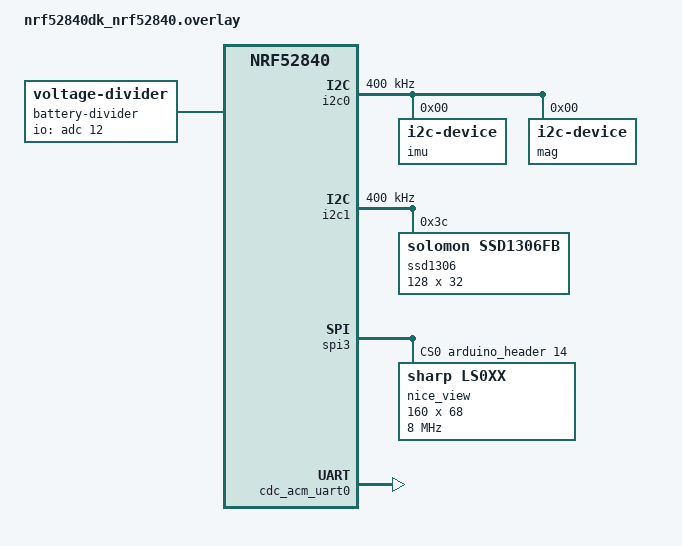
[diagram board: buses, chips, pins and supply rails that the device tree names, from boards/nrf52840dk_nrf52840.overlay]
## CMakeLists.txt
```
#
# Copyright (c) 2023 Nordic Semiconductor
#
# SPDX-License-Identifier: LicenseRef-Nordic-5-Clause
#
cmake_minimum_required(VERSION 3.20.0)

# Configure VERSION from repository branch and tag
find_package(Git)

if(GIT_EXECUTABLE)
  execute_process(
    COMMAND ${GIT_EXECUTABLE} branch --show-current
    WORKING_DIRECTORY ${CMAKE_SOURCE_DIR}
    OUTPUT_VARIABLE GIT_BRANCH
    )
  execute_process(
    COMMAND ${GIT_EXECUTABLE} describe --dirty --tags --long --match [0-9]*.[0-9]*.[0-9]*
    WORKING_DIRECTORY ${CMAKE_SOURCE_DIR}
    OUTPUT_VARIABLE GIT_VERSION
    )
endif()

if(GIT_BRANCH STREQUAL "")
  set(GIT_BRANCH unknown)
  message(WARNING "Unknown Git Branch")
endif()

if(GIT_VERSION STREQUAL "")
  set(GIT_VERSION 0.0.0-0)
  message(WARNING "Unknown Tag/Version")
endif()

string(STRIP ${GIT_BRANCH} GIT_BRANCH)
string(STRIP ${GIT_VERSION} GIT_VERSION)
string(REPLACE "-" ";" GIT_VERSION ${GIT_VERSION})
list(GET GIT_VERSION 0 GIT_RELEASE)
list(GET GIT_VERSION 1 GIT_TWEAK)
string(REPLACE "v" "" GIT_RELEASE ${GIT_RELEASE})
string(REPLACE "." ";" GIT_RELEASE ${GIT_RELEASE})
list(GET GIT_RELEASE 0 GIT_MAJOR)
list(GET GIT_RELEASE 1 GIT_MINOR)
list(GET GIT_RELEASE 2 GIT_PATCH)

configure_file(${CMAKE_SOURCE_DIR}/VERSION_SRC ${CMAKE_SOURCE_DIR}/VERSION @ONLY)

# Zephyr
find_package(Zephyr REQUIRED HINTS $ENV{ZEPHYR_BASE})
project(NONE)

# NORDIC SDK APP START
FILE(GLOB_RECURSE app_sources src/*.c)
target_sources(app PRIVATE ${app_sources})

# NORDIC SDK APP END

FILE(GLOB_RECURSE files vqf-c/src/*.c)
target_sources(app PRIVATE ${files})

target_include_directories(app PRIVATE src)
target_include_directories(app PRIVATE vqf-c/src)

# Force recompile for updated build timestamp
add_custom_target(touch_util_h ALL
    COMMAND ${CMAKE_COMMAND} -E touch ${CMAKE_SOURCE_DIR}/src/build_defines.h
)

# clangd wants compile_commands.json in the root of build directory
# try to find the build root clangd will be happy with
cmake_path(GET CMAKE_CURRENT_BINARY_DIR PARENT_PATH build_dir)
cmake_path(COMPARE ${CMAKE_CURRENT_LIST_DIR} NOT_EQUAL ${build_dir} build_dir_is_subdirectory)

if(build_dir_is_subdirectory)
  add_custom_target(link_target ALL
    COMMAND ${CMAKE_COMMAND} -E create_symlink ${CMAKE_CURRENT_BINARY_DIR}/compile_commands.json ${build_dir}/compile_commands.json)
endif()
```

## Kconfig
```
#
# Copyright (c) 2023 Nordic Semiconductor
#
# SPDX-License-Identifier: LicenseRef-Nordic-5-Clause
#

config USE_SLIMENRF_CONSOLE
    bool "Use basic console"
    default y
    help
        Use basic console for commands.

config BATTERY_CHARGER_HAS_NTC
    bool "Battery thermistor"
    help
      Flag for battery NTC thermistor availability.

choice
    prompt "Battery voltage mapping"
    default BATTERY_NO_MAPPING

config BATTERY_USE_REG_BUCK_MAPPING
    bool "Use buck regulator mapping (3.7V battery, DCDC)"
    help
      Use a constant power mapping for battery voltage.
      Preffered for systems with a buck regulator.
      Measured at a system voltage of 3.0V.

config BATTERY_USE_REG_LDO_MAPPING
    bool "Use LDO linear regulator mapping (3.7V battery, LDO)"
    help
      Use a constant current mapping for battery voltage.
      Preferred for systems with a linear regulator.

config BATTERY_NO_MAPPING
    bool "Disable battery voltage mapping"
    help
      Always map to 100% battery. Disables battery monitoring.

endchoice

config BATTERY_LOW_RUNTIME_THRESHOLD
    int "Low battery runtime threshold (ms)"
    default 10800000
    help
      Trigger low battery when estimated runtime falls below threshold.
      If estimated runtime is not available, low battery will trigger under 10% estimated state of charge.

choice
    prompt "Status LED color mapping"
    default LED_TRI_COLOR

config LED_RGB_COLOR
    bool "Use RGB color mapping"
    help
        Use RGB or RG color mapping for LED status if available.

config LED_TRI_COLOR
    bool "Use default color mapping"
    help
        Use the default color mapping for LED status.

endchoice

menu "Status LED default status color"
    depends on LED_RGB_COLOR

config LED_DEFAULT_COLOR_R
    int "Red value"
    range 0 10000
    default 4000
    depends on LED_RGB_COLOR
    help
        Red color for default status.
        Valid range is 0 to 10000.

config LED_DEFAULT_COLOR_G
    int "Green value"
    range 0 10000
    default 6000
    depends on LED_RGB_COLOR
    help
        Green color for default status.
        Valid range is 0 to 10000.

config LED_DEFAULT_COLOR_B
    int "Blue value"
    range 0 10000
    default 0
    depends on LED_RGB_COLOR
    help
        Blue color for default status.
        Valid range is 0 to 10000.

endmenu

config USER_EXTRA_ACTIONS
    bool "Multiple press actions"
    help
        Allow user to use multiple presses to calibrate, pair, or enter DFU.
        By default, pairing is available when holding down sw0 for 5 seconds.
        By default, DFU is available when holding down sw0 and plugging in a USB cable.

config IGNORE_RESET
    bool "Ignore reset"
    default y
    help
        If sw0 is available, don't perform any extra actions on reset.

config USER_SHUTDOWN
    bool "User shutdown support"
    default y
    help
        Allow user to use reset or sw0 to shutdown.

config USE_IMU_WAKE_UP
    bool "IMU wake up support"
    default y
    help
        Use IMU wake up state if IMU wake up is present.

config DELAY_SLEEP_ON_STATUS
    bool "Delay IMU wake up mode on status flags"
    default y
    depends on USE_IMU_WAKE_UP
    help
        Delay IMU wake up state if there is an active status flag or in pairing mode.

config WOM_USE_DCDC
    bool "Use DCDC in IMU wake up mode"
    depends on USE_IMU_WAKE_UP
    help
        Use DCDC instead of LDO in IMU wake up state if it is more efficient.

config CONNECTION_TIMEOUT_DELAY
    int "Connection timeout delay (ms)"
    default 600000
    depends on USER_SHUTDOWN
    help
        Connection timeout duration when receiver is not detected.

choice
    prompt "Sensor rotation"
    default SENSOR_ROTATION_90

config SENSOR_ROTATION_0
    bool "0 degrees"

config SENSOR_ROTATION_90
    bool "90 degrees"

config SENSOR_ROTATION_180
    bool "180 degrees"

config SENSOR_ROTATION_270
    bool "270 degrees"

config SENSOR_ROTATION_0_FLIPPED
    bool "0 degrees flipped"

config SENSOR_ROTATION_90_FLIPPED
    bool "90 degrees flipped"

config SENSOR_ROTATION_180_FLIPPED
    bool "180 degrees flipped"

config SENSOR_ROTATION_270_FLIPPED
    bool "270 degrees flipped"

endchoice

menu "Sensor power saving"

config SENSOR_LP_TIMEOUT
    int "Sensor low power delay (ms)"
    default 500
    help
        Low power timeout during no motion.

config SENSOR_USE_LOW_POWER_2
    bool "Use additional low power modes"
    help
        Use a higher latency sensor mode during no motion.

config USE_IMU_TIMEOUT
    bool "Use IMU wake up state"
    default y
    depends on USE_IMU_WAKE_UP
    help
        Use IMU wake up state during no motion.

config IMU_TIMEOUT_RAMP_MIN
    int "Sensor timeout minimum delay (ms)"
    default 5000
    depends on USE_IMU_TIMEOUT || SENSOR_USE_LOW_POWER_2
    help
        Minimum timeout during no motion. Initial period on wake up.

config IMU_TIMEOUT_RAMP_MAX
    int "Sensor timeout maximum delay (ms)"
    default 15000
    depends on USE_IMU_TIMEOUT || SENSOR_USE_LOW_POWER_2
    help
        Maximum timeout during no motion.

config USE_ACTIVE_TIMEOUT
    bool "Use activity timeout"
    default y
    depends on USE_IMU_WAKE_UP || USER_SHUTDOWN
    help
        Delay IMU wake up state or user shutdown during activity.

choice
    prompt "Activity timeout mode"
    default SLEEP_ON_ACTIVE_TIMEOUT
    depends on USE_ACTIVE_TIMEOUT

config SLEEP_ON_ACTIVE_TIMEOUT
    bool "IMU wake up"
    depends on USE_IMU_WAKE_UP
    help
        Use IMU wake up state when activity timeout elapses.

config SHUTDOWN_ON_ACTIVE_TIMEOUT
    bool "User shutdown"
    depends on USER_SHUTDOWN
    help
        Use user shutdown when activity timeout elapses.

endchoice

config ACTIVE_TIMEOUT_THRESHOLD
    int "Activity timeout threshold (ms)"
    default 15000
    depends on USE_ACTIVE_TIMEOUT
    help
        Trigger activity timeout after a certain threshold of activity.

config ACTIVE_TIMEOUT_DELAY
    int "Activity timeout delay (ms)"
    default 900000
    depends on USE_ACTIVE_TIMEOUT
    help
        Activity timeout duration when triggered.

endmenu

config SENSOR_ACCEL_ODR
    int "Accelerometer output data rate (Hz)"
    default 100
    help
        Requested accelerometer output data rate. Actual rate will be raised to the nearest supported rate.
        A higher rate will increase the time to read and process sensor data.

config SENSOR_GYRO_ODR
    int "Gyrometer output data rate (Hz)"
    default 200
    help
        Requested gyrometer output data rate. Actual rate will be raised to the nearest supported rate.
        A higher rate will increase the time to read and process sensor data.
        A lower rate is recommended for IMUs with poor gyrometer rate noise density. (e.g. BMI270, LSM6DS3TR-C)

config SENSOR_ACCEL_FS
    int "Accelerometer full scale (g)"
    default 4
    help
        Requested accelerometer full scale. Actual scale will be raised to the nearest supported scale.
        A lower scale may improve noise performance, but is more likely to saturate.

config SENSOR_GYRO_FS
    int "Gyrometer full scale (dps)"
    default 1000
    help
        Requested gyrometer full scale. Actual scale will be raised to the nearest supported scale.
        A lower scale may improve noise performance, but is more likely to saturate.

config SENSOR_USE_MAG
    bool "Magnetometer support"
    default y
    help
        Use magnetometer if it is present.

config USE_SENSOR_CLOCK
    bool "Use external IMU clock"
    default y
    help
        Use external IMU clock if it is present.

choice
    prompt "Sensor fusion"
    default SENSOR_USE_VQF
    help
        Select the sensor fusion method.

config SENSOR_USE_VQF
    bool "Use VQF"
    help
        Use VQF for sensor fusion.
        Based on Kalman filter.

endchoice

config SENSOR_USE_6_SIDE_CALIBRATION
    bool "Use 6-side calibration"
    default y
    depends on USE_SLIMENRF_CONSOLE
    help
        Use 6-side calibration for accelerometer.
        Calibration can be completed through the basic console.

config RADIO_TX_POWER
    int "Radio output power (dBm)"
    default 8
    help
        Radio output power level.
        A lower value may reduce power consumption.

config CONNECTION_OVER_HID
    bool "Use HID for data output"
    help
        Use HID if available.
        Otherwise, use ESB only.

choice CLOCK_SOURCE_LFCLK
    prompt "LF clock source for TDMA"
    default CLOCK_SOURCE_LFCLK_FULL_SWING
    help
        Chose which crystal or oscillator is connected
        to XL1/XL2 pins, if any. External 32.768kHz crystal
        or oscillator is recommended.

config CLOCK_SOURCE_LFCLK_XTAL
    bool "External passive crystal"

config CLOCK_SOURCE_LFCLK_LOW_SWING
    bool "External low-swing oscillator"

config CLOCK_SOURCE_LFCLK_FULL_SWING
    bool "External full-swing oscillator"

config CLOCK_SOURCE_LFCLK_SYNTH
    bool "Synthesized from internal HF clock (high power consumption)"

config CLOCK_SOURCE_LFCLK_RC
    bool "Internal RC clock (bad performance)"

endchoice

config BTF_DUT
    bool "Test mode for certification"

source "Kconfig.zephyr"
```

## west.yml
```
manifest:
  version: "1.2"
  projects:

    # nRF-Connect SDK
    - name: sdk-nrf
      path: nrf
      url: https://github.com/SlimeVR/sdk-nrf.git
      revision: v3.1-slimevr
      import: true
```

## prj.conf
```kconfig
#CONFIG_NCS_SAMPLES_DEFAULTS
CONFIG_ASSERT=y
CONFIG_ASSERT_NO_COND_INFO=y
CONFIG_ASSERT_NO_MSG_INFO=y
CONFIG_RESET_ON_FATAL_ERROR=y

CONFIG_NCS_APPLICATION_BOOT_BANNER_STRING="SlimeVR-Tracker-nRF"
#CONFIG_NCS_BOOT_BANNER=n
CONFIG_BOOT_BANNER=n

#need to enable for nRF54L
CONFIG_NRFX_DPPI10=y

CONFIG_ADC=y
CONFIG_ADC_NRFX_SAADC=y
CONFIG_FPU=y
CONFIG_I2C=y
CONFIG_SPI=y
CONFIG_PINCTRL=y
CONFIG_SENSOR=y
CONFIG_ESB=y

CONFIG_CMSIS_DSP=y
CONFIG_CMSIS_DSP_BASICMATH=y
CONFIG_CMSIS_DSP_CONTROLLER=y
CONFIG_CMSIS_DSP_FASTMATH=y
CONFIG_CMSIS_DSP_SUPPORT=y

CONFIG_NVS=y
CONFIG_NVS_LOOKUP_CACHE=y
CONFIG_NVS_INIT_BAD_MEMORY_REGION=y

CONFIG_POWEROFF=y
CONFIG_REBOOT=y

CONFIG_FLASH=y
CONFIG_FLASH_PAGE_LAYOUT=y
CONFIG_FLASH_MAP=y

CONFIG_SETTINGS=y
CONFIG_SETTINGS_RUNTIME=y
CONFIG_SETTINGS_NONE=y

CONFIG_MPU_ALLOW_FLASH_WRITE=y

CONFIG_RETAINED_MEM=y

CONFIG_USE_SEGGER_RTT=y
CONFIG_LOG=y
#CONFIG_PRINTK=n
CONFIG_LOG_MODE_DEFERRED=y
CONFIG_LOG_SPEED=y
CONFIG_LOG_BACKEND_RTT=y
CONFIG_CBPRINTF_FP_SUPPORT=y
CONFIG_ADC_LOG_LEVEL_OFF=y
CONFIG_LOG_FUNC_NAME_PREFIX_ERR=y
CONFIG_LOG_BUFFER_SIZE=8192
CONFIG_LOG_BACKEND_UART_AUTOSTART=y
CONFIG_LOG_PROCESS_THREAD_SLEEP_MS=50
CONFIG_LOG_PROCESS_THREAD_STACK_SIZE=1024

CONFIG_PWM=y
CONFIG_GPIO=y

CONFIG_CRC=y

CONFIG_NEWLIB_LIBC=y
#deprecated?
#CONFIG_NRFX_TIMER1=y

# Use uncalibrated RC clock on boot, will switch to external oscillator in the app after boot
CONFIG_CLOCK_CONTROL_NRF_K32SRC_RC=y
CONFIG_CLOCK_CONTROL_NRF_K32SRC_RC_CALIBRATION=y
CONFIG_CLOCK_CONTROL_NRF_K32SRC_SYNTH=n

# dont need it
CONFIG_CRYPTO=n

# set timeout for 25ms, sufficient for ~1000 bytes
CONFIG_I2C_NRFX_TRANSFER_TIMEOUT=25

CONFIG_USB_DEVICE_HID=y
CONFIG_USB_DEVICE_VID=0x1209
CONFIG_USB_DEVICE_PID=0x7692
CONFIG_USB_HID_BOOT_PROTOCOL=y
CONFIG_USB_DEVICE_INITIALIZE_AT_BOOT=n
CONFIG_USB_CDC_ACM=y
CONFIG_UART_INTERRUPT_DRIVEN=y
CONFIG_USB_WORKQUEUE_STACK_SIZE=512

CONFIG_SERIAL=y
CONFIG_CONSOLE=y
CONFIG_RTT_CONSOLE=y
CONFIG_UART_CONSOLE=y
CONFIG_UART_LINE_CTRL=y
# fit "write all <base64:173>"
CONFIG_CONSOLE_INPUT_MAX_LINE_LEN=256

CONFIG_USB_DRIVER_LOG_LEVEL_ERR=y
CONFIG_USB_DEVICE_LOG_LEVEL_ERR=y
CONFIG_USB_CDC_ACM_LOG_LEVEL_OFF=y

CONFIG_LOG_BACKEND_UART=y

CONFIG_CONSOLE_SUBSYS=y
CONFIG_CONSOLE_GETLINE=y

CONFIG_NVS_LOG_LEVEL_WRN=y
CONFIG_USB_HID_LOG_LEVEL_WRN=y

CONFIG_USB_DEVICE_SOF=y
CONFIG_USB_HID_REPORTS=256

#CONFIG_USB_HID_POLL_INTERVAL_MS=1
CONFIG_USB_HID_POLL_INTERVAL_MS=0
CONFIG_HID_INTERRUPT_EP_MPS=64
#CONFIG_ENABLE_HID_INT_OUT_EP=y

CONFIG_SYSTEM_WORKQUEUE_STACK_SIZE=4096
CONFIG_MAIN_STACK_SIZE=1024
#crashing on nrf54l at 512

CONFIG_THREAD_NAME=y

CONFIG_HEAP_MEM_POOL_SIZE=2048
CONFIG_ISR_STACK_SIZE=1024

CONFIG_PM_DEVICE=y

CONFIG_BASE64=y

#about 20KB saved
#CONFIG_LTO=y
#CONFIG_ISR_TABLES_LOCAL_DECLARATION=y

#CONFIG_USE_IMU_TIMEOUT=n

CONFIG_GPIO_LV164=y
CONFIG_LOG_MODE_IMMEDIATE=n

### Clock ###
CONFIG_CLOCK_CONTROL=y
CONFIG_CLOCK_CONTROL_NRF=y

CONFIG_NRFX_CLOCK=y
CONFIG_NRF_GRTC_TIMER=y
CONFIG_NRF_GRTC_START_SYSCOUNTER=y
CONFIG_NRFX_GRTC=y
CONFIG_NRFX_CLOCK_LF_SRC_RC=y

CONFIG_CLOCK_CONTROL_NRF_K32SRC_SYNTH=n
CONFIG_CLOCK_CONTROL_NRF_K32SRC_RC=y
CONFIG_CLOCK_CONTROL_NRF_K32SRC_XTAL=n

CONFIG_CLOCK_CONTROL_NRF_K32SRC_500PPM=y
CONFIG_CLOCK_CONTROL_NRF_K32SRC_RC_CALIBRATION=y
CONFIG_CLOCK_CONTROL_NRF_CALIBRATION_LF_ALWAYS_ON=y

CONFIG_SYS_CLOCK_HW_CYCLES_PER_SEC=1000000
CONFIG_SYS_CLOCK_TICKS_PER_SEC=32768
CONFIG_LED_STRIP=n

CONFIG_LOG_MODE_IMMEDIATE=n

CONFIG_EXCEPTION_STACK_TRACE=y
CONFIG_RESET_ON_FATAL_ERROR=n
CONFIG_THREAD_ANALYZER=y
CONFIG_THREAD_STACK_INFO=y
CONFIG_INIT_STACKS=y
CONFIG_HW_STACK_PROTECTION=y
```

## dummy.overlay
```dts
// dummy flash partitions for mcuboot compilation
&flash0 {
	partitions {
		compatible = "fixed-partitions";
		#address-cells = <1>;
		#size-cells = <1>;

		slot0_partition: partition@0 {
			reg = <0 1>;
		};
	};
};
```

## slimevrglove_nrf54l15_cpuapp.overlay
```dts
/* For more help, browse the devicetree documentation at https://docs.zephyrproject.org/latest/build/dts/index.html
 * You can also visit the nRF DeviceTree extension documentation at https://docs.nordicsemi.com/bundle/nrf-connect-vscode/page/guides/ncs_configure_app.html#devicetree-support-in-the-extension
 */
```

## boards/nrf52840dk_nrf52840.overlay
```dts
&pwm0_default {
	group1 {
		psels = <NRF_PSEL(PWM_OUT0, 0, 13)>,
			<NRF_PSEL(PWM_OUT1, 0, 14)>,
			<NRF_PSEL(PWM_OUT2, 0, 15)>;
		nordic,drive-mode = <NRF_DRIVE_D0S1>;
		nordic,invert;
	};
};

&pwm0_sleep {
	group1 {
		psels = <NRF_PSEL(PWM_OUT0, 0, 13)>,
			<NRF_PSEL(PWM_OUT1, 0, 14)>,
			<NRF_PSEL(PWM_OUT2, 0, 15)>;
	};
};

&i2c0_default {
	group1 {
		bias-disable;
	};
};

&i2c0_sleep {
	group1 {
		bias-disable;
	};
};

/ {
	chosen {
		zephyr,console = &cdc_acm_uart0;
		zephyr,shell-uart = &cdc_acm_uart0;
		zephyr,display = &nice_view;
	};

	pwmleds {
		pwm_led1: pwm_led_1 {
			pwms = <&pwm0 1 PWM_MSEC(20) PWM_POLARITY_INVERTED>;
		};
		pwm_led2: pwm_led_2 {
			pwms = <&pwm0 2 PWM_MSEC(20) PWM_POLARITY_INVERTED>;
		};
	};

	battery-divider {
		compatible = "voltage-divider";
		status = "okay";
		io-channels = <&adc 12>; // Measure VDDHDIV5
		output-ohms = <1>;
		full-ohms = <2>;
	};

	aliases {
		pwm-led1 = &pwm_led1;
		pwm-led2 = &pwm_led2;
	};
};

&i2c0 {
	compatible = "nordic,nrf-twim";
	zephyr,concat-buf-size = <1023>;
	zephyr,flash-buf-max-size = <1023>;
	clock-frequency = <I2C_BITRATE_FAST>;

	imu: imu@0 { // any address out of range (00, 7f, etc. will search all addresses and stored address first if available, specify an address here to search first otherwise
		compatible = "i2c-device";
		label = "imu";
		reg = <0>;
	};

	mag: mag@0 {
		compatible = "i2c-device";
		label = "mag";
		reg = <0>;
	};

};

&i2c1 {
	compatible = "nordic,nrf-twim";
	status = "okay";
	clock-frequency = <I2C_BITRATE_FAST>;
	zephyr,concat-buf-size = <4096>;

	ssd1306: ssd1306@3c {
		status = "okay";
		compatible = "solomon,ssd1306fb";
		reg = <0x3c>;
		width = <128>;
		height = <32>;
		segment-offset = <0>;
		page-offset = <0>;
		display-offset = <0>;
		multiplex-ratio = <31>;
		segment-remap;
		com-invdir;
		com-sequential;
		prechargep = <0x22>;
	};
};

&spi1 {
	status = "disabled";
};

&spi3 {
	status = "okay";
    cs-gpios = <&arduino_header 14 GPIO_ACTIVE_HIGH>;
    pinctrl-0 = <&spi2_default>;
    pinctrl-1 = <&spi2_sleep>;
    nice_view: ls0xx@0 {
        compatible = "sharp,ls0xx";
		spi-max-frequency = <DT_FREQ_M(8)>;
        reg = <0>;
        width = <160>;
        height = <68>;
    };
};

/delete-node/ &qspi;
/delete-node/ &spi2;

/*
&spi3 {
	status = "okay";
    cs-gpios = <&arduino_header 16 GPIO_ACTIVE_LOW>;
    pinctrl-0 = <&spi3_default>;
    pinctrl-1 = <&spi3_sleep>;
	imu_spi: imu_spi@0 {
		compatible = "vnd,spi-device";
		spi-max-frequency = <DT_FREQ_M(32)>;
		label = "imu-spi";
		reg = <0>;
	};
};
*/

&usbd {
	cdc_acm_uart0: cdc_acm_uart0 {
		compatible = "zephyr,cdc-acm-uart";
	};
};
```

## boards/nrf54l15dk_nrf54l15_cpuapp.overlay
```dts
&pinctrl {
	i2c0_default: i2c0_default {
		group1 {
			psels = <NRF_PSEL(TWIM_SDA, 1, 5)>,
				<NRF_PSEL(TWIM_SCL, 1, 7)>;
		};
	};

	i2c0_sleep: i2c0_sleep {
		group1 {
			psels = <NRF_PSEL(TWIM_SDA, 1, 5)>,
				<NRF_PSEL(TWIM_SCL, 1, 7)>;
			low-power-enable;
		};
	};
};

&pwm20_default {
	group1 {
		psels = <NRF_PSEL(PWM_OUT0, 1, 10)>,
			<NRF_PSEL(PWM_OUT1, 1, 14)>;
	};
};

&pwm20_sleep {
	group1 {
		psels = <NRF_PSEL(PWM_OUT0, 1, 10)>,
			<NRF_PSEL(PWM_OUT1, 1, 14)>;
	};
};

/ {
	pwmleds {
		pwm_led0: pwm_led_0 {
			pwms = <&pwm20 1 PWM_MSEC(20) PWM_POLARITY_NORMAL>;
		};
	};

	battery-divider {
		compatible = "voltage-divider";
		status = "okay";
		io-channels = <&adc 12>; // Measure VDDHDIV5
		output-ohms = <1>;
		full-ohms = <2>;
	};
};

&i2c20 {
	compatible = "nordic,nrf-twim";
	status = "okay";
	zephyr,concat-buf-size = <1023>;
	zephyr,flash-buf-max-size = <1023>;
	clock-frequency = <I2C_BITRATE_FAST>;
	pinctrl-0 = <&i2c0_default>;
	pinctrl-1 = <&i2c0_sleep>;
	pinctrl-names = "default", "sleep";

	imu: imu@0 { // any address out of range (00, 7f, etc. will search all addresses and stored address first if available, specify an address here to search first otherwise
		compatible = "i2c-device";
		label = "imu";
		reg = <0>;
	};

	mag: mag@0 {
		compatible = "i2c-device";
		label = "mag";
		reg = <0>;
	};
};

&spi00 {
	/delete-node/ mx25r6435f@0;

	imu_spi: imu_spi@0 {
		compatible = "vnd,spi-device";
		spi-max-frequency = <DT_FREQ_M(24)>;
		label = "imu-spi";
		reg = <0>;
	};
};

&uart20 {
	status = "disabled";
};
```

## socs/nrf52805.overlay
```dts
/ {
	sram0@20005800 {
		compatible = "zephyr,memory-region", "mmio-sram";
		reg = <0x20005800 DT_SIZE_K(2)>;
		zephyr,memory-region = "RetainedMem";
		status = "okay";

		retainedmem0: retainedmem {
			compatible = "zephyr,retained-ram";
			status = "okay";
		};
	};

	aliases {
		retainedmemdevice = &retainedmem0;
	};
};

&sram0 {
	/* Shrink SRAM size to avoid overlap with retained memory region */
	reg = <0x20000000 DT_SIZE_K(22)>;
};
```

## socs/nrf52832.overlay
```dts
/ {
	sram0@20007000 {
		compatible = "zephyr,memory-region", "mmio-sram";
		reg = <0x20007000 DT_SIZE_K(4)>;
		zephyr,memory-region = "RetainedMem";
		status = "okay";

		retainedmem0: retainedmem {
			compatible = "zephyr,retained-ram";
			status = "okay";
		};
	};

	aliases {
		retainedmemdevice = &retainedmem0;
	};
};

&sram0 {
	/* Shrink SRAM size to avoid overlap with retained memory region */
	reg = <0x20000000 DT_SIZE_K(28)>;
};
```

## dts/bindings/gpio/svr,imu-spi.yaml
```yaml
description: "imu with added properties"

compatible: "svr,imu-spi"

include: spi-device.yaml

properties:
  sensor-position:
    type: int
    required: false
    description: Value of sensor position as described in sensor_position.h
```

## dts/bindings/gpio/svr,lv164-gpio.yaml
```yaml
compatible: "svr,lv164-gpio"

description: "Driver to make reading from multiple imus easier"

include: [gpio-controller.yaml, base.yaml]

properties:
  dsb-gpios:
    type: phandle-array
    required: true
    description: Serial data input pin (DS) of the shift register.

  cp-gpios:
    type: phandle-array
    required: true
    description: Shift clock pin (CP) of the shift register.

  num-outputs:
    type: int
    required: true
    description: Number of output bits (8 for a single 74LV164, 16 if two are daisy-chained, etc).

  "#gpio-cells":
    const: 2

gpio-cells:
  - pin
  - flags
```

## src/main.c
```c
/*
	SlimeVR Code is placed under the MIT license
	Copyright (c) 2025 SlimeVR Contributors

	Permission is hereby granted, free of charge, to any person obtaining a copy
	of this software and associated documentation files (the "Software"), to deal
	in the Software without restriction, including without limitation the rights
	to use, copy, modify, merge, publish, distribute, sublicense, and/or sell
	copies of the Software, and to permit persons to whom the Software is
	furnished to do so, subject to the following conditions:

	The above copyright notice and this permission notice shall be included in
	all copies or substantial portions of the Software.

	THE SOFTWARE IS PROVIDED "AS IS", WITHOUT WARRANTY OF ANY KIND, EXPRESS OR
	IMPLIED, INCLUDING BUT NOT LIMITED TO THE WARRANTIES OF MERCHANTABILITY,
	FITNESS FOR A PARTICULAR PURPOSE AND NONINFRINGEMENT. IN NO EVENT SHALL THE
	AUTHORS OR COPYRIGHT HOLDERS BE LIABLE FOR ANY CLAIM, DAMAGES OR OTHER
	LIABILITY, WHETHER IN AN ACTION OF CONTRACT, TORT OR OTHERWISE, ARISING FROM,
	OUT OF OR IN CONNECTION WITH THE SOFTWARE OR THE USE OR OTHER DEALINGS IN
	THE SOFTWARE.
*/
#include "globals.h"
#include "system/system.h"
//#include "timer.h"
#include "connection/esb.h"
#include "sensor/sensor.h"

#include <zephyr/sys/reboot.h>

LOG_MODULE_REGISTER(main, LOG_LEVEL_INF);

#if DT_NODE_HAS_PROP(DT_ALIAS(sw0), gpios)
#define BUTTON_EXISTS true
#endif

#define DFU_EXISTS CONFIG_BUILD_OUTPUT_UF2 || CONFIG_BOARD_HAS_NRF5_BOOTLOADER
#define ADAFRUIT_BOOTLOADER CONFIG_BUILD_OUTPUT_UF2

int main(void)
{
#ifdef NRF_RESET
	bool reset_pin_reset = NRF_RESET->RESETREAS & RESET_RESETREAS_RESETPIN_Msk;
	NRF_RESET->RESETREAS = NRF_RESET->RESETREAS; // Clear RESETREAS
#else
	bool reset_pin_reset = NRF_POWER->RESETREAS & POWER_RESETREAS_RESETPIN_Msk;
	NRF_POWER->RESETREAS = NRF_POWER->RESETREAS; // Clear RESETREAS
#endif

#if BUTTON_EXISTS
	if (CONFIG_0_SETTINGS_READ(CONFIG_0_IGNORE_RESET))
		reset_pin_reset = false;
#endif

	set_led(SYS_LED_PATTERN_ONESHOT_WAKE, SYS_LED_PRIORITY_BOOT); // Boot LED

	uint8_t reboot_counter = reboot_counter_read();
	bool booting_from_shutdown = !reboot_counter && (reset_pin_reset || button_read()); // 0 means from user shutdown or failed ram validation

	/* if button is not held after booting from shutdown, power off again
	 * if button press is normal, continue boot
	 * if button is held for 1 second, reset pairing and continue boot
	 * if button is held but tracker was waking (not booting from shutdown) ignore the press // TODO: this should pass on to regular handler (e.g. intent to shutdown)
	 */

	if (booting_from_shutdown)
	{
		set_led(SYS_LED_PATTERN_ONESHOT_POWERON, SYS_LED_PRIORITY_BOOT);
		if (button_read())
		{
			set_status(SYS_STATUS_BUTTON_PRESSED, true); // prevent going to sleep while still holding
			int64_t start_time = k_uptime_get();
			while (button_read())
			{
				if (k_uptime_get() - start_time > 1000)
				{
					LOG_INF("Pairing requested");
					pairing_request_pair();
					break;
				}
				k_msleep(1);
			}
			if (CONFIG_0_SETTINGS_READ(CONFIG_0_USER_SHUTDOWN) && k_uptime_get() - start_time < 50) // debounce // TODO: does sense pin stay configured?
				sys_request_system_silent_off(false);
			set_status(SYS_STATUS_BUTTON_PRESSED, false);
		}
	}

	bool docked = dock_read();

	uint8_t reset_mode = -1;

	if (reboot_counter == 0)
		reboot_counter = 100;
	else if (reboot_counter > 200)
		reboot_counter = 200; // How did you get here
	reset_mode = reboot_counter - 100;
	if (reset_pin_reset && !docked) // Count pin resets while not docked
	{
		reboot_counter++;
		reboot_counter_write(reboot_counter);
		LOG_INF("Reset count: %u", reboot_counter);
#if ADAFRUIT_BOOTLOADER
#if BUTTON_EXISTS
		if (!CONFIG_0_SETTINGS_READ(CONFIG_0_IGNORE_RESET))
			NRF_POWER->GPREGRET = 0x6d; // Using Adafruit bootloader, skip DFU if reset button could be used
#else
		NRF_POWER->GPREGRET = 0x6d; // Using Adafruit bootloader, skip DFU since reset button is used
#endif
#endif
		k_msleep(1000); // Wait before clearing counter and continuing
	}
	reboot_counter_write(100);
	if (!reset_pin_reset && reset_mode == 0) // Only need to check once, if the button is pressed again an interrupt is triggered from before
		reset_mode = -1; // Cancel reset_mode (shutdown)

	if (CONFIG_0_SETTINGS_READ(CONFIG_0_USER_SHUTDOWN))
	{
		bool charging = chg_read();
		bool charged = stby_read();
		bool plugged = vin_read();

		if (reset_mode == 0 && !booting_from_shutdown && !charging && !charged && !plugged) // Reset mode user shutdown, only if unplugged and undocked
			sys_user_shutdown();
	}

	sys_reset_mode(reset_mode);

	return 0;
}
```

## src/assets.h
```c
#include <stdint.h>

// TODO: Unifont is licensed under GNU, may need to be replaced
static const uint8_t unifont[] = {0x00, 0x00, 0x00, 0xfe, 0x00, 0x00, 0x00, 0x00, 0x07, 0x00, 0x00, 0x00, 0x07, 0x00, 0x90, 0xf0, 0x9e, 0x90, 0xf0, 0x9e, 0x00, 0x18, 0x24, 0x24, 0xfe, 0x44, 0x44, 0x88, 0x0c, 0x12, 0x92, 0x6c, 0x90, 0x8c, 0x02, 0x80, 0x4c, 0x32, 0x62, 0x92, 0x0c, 0xc0, 0x00, 0x00, 0x00, 0x07, 0x00, 0x00, 0x00, 0x00, 0x00, 0xf8, 0x06, 0x01, 0x00, 0x00, 0x00, 0x01, 0x06, 0xf8, 0x00, 0x00, 0x00, 0x10, 0xa0, 0x40, 0xf8, 0x40, 0xa0, 0x10, 0x40, 0x40, 0x40, 0xf8, 0x40, 0x40, 0x40, 0x00, 0x00, 0x00, 0x00, 0x00, 0x00, 0x00, 0x00, 0x40, 0x40, 0x40, 0x40, 0x00, 0x00, 0x00, 0x00, 0x00, 0x00, 0x00, 0x00, 0x00, 0x00, 0x00, 0xc0, 0x30, 0x08, 0x06, 0x00, 0xf8, 0x84, 0x42, 0x22, 0x14, 0xf8, 0x00, 0x00, 0x08, 0x04, 0xfe, 0x00, 0x00, 0x00, 0x0c, 0x82, 0x42, 0x22, 0x22, 0x1c, 0x00, 0x0c, 0x02, 0x22, 0x22, 0x22, 0xdc, 0x00, 0xe0, 0x90, 0x88, 0x84, 0xfe, 0x80, 0x00, 0x3e, 0x22, 0x22, 0x22, 0x22, 0xc2, 0x00, 0xf8, 0x24, 0x22, 0x22, 0x22, 0xc0, 0x00, 0x02, 0x02, 0x02, 0x82, 0x72, 0x0e, 0x00, 0xdc, 0x22, 0x22, 0x22, 0x22, 0xdc, 0x00, 0x1c, 0x22, 0x22, 0x22, 0x22, 0xfc, 0x00, 0x00, 0x00, 0x18, 0x18, 0x00, 0x00, 0x00, 0x00, 0x00, 0x18, 0x18, 0x00, 0x00, 0x00, 0x00, 0x40, 0xa0, 0x10, 0x08, 0x04, 0x00, 0x10, 0x10, 0x10, 0x10, 0x10, 0x10, 0x00, 0x04, 0x08, 0x10, 0xa0, 0x40, 0x00, 0x00, 0x0c, 0x02, 0x02, 0xc2, 0x22, 0x1c, 0x00, 0xf8, 0x04, 0xf2, 0x0a, 0x12, 0xfc, 0x00, 0xf0, 0x4c, 0x42, 0x42, 0x4c, 0xf0, 0x00, 0xfe, 0x22, 0x22, 0x22, 0x22, 0xdc, 0x00, 0xfc, 0x02, 0x02, 0x02, 0x02, 0x0c, 0x00, 0xfe, 0x02, 0x02, 0x02, 0x04, 0xf8, 0x00, 0xfe, 0x22, 0x22, 0x22, 0x22, 0x02, 0x00, 0xfe, 0x22, 0x22, 0x22, 0x22, 0x02, 0x00, 0xfc, 0x02, 0x02, 0x42, 0x42, 0xcc, 0x00, 0xfe, 0x20, 0x20, 0x20, 0x20, 0xfe, 0x00, 0x00, 0x02, 0x02, 0xfe, 0x02, 0x02, 0x00, 0x00, 0x00, 0x02, 0x02, 0xfe, 0x02, 0x02, 0xfe, 0x60, 0x90, 0x08, 0x04, 0x02, 0x00, 0xfe, 0x00, 0x00, 0x00, 0x00, 0x00, 0x00, 0xfe, 0x18, 0x60, 0x60, 0x18, 0xfe, 0x00, 0xfe, 0x0c, 0x30, 0xc0, 0x00, 0xfe, 0x00, 0xfc, 0x02, 0x02, 0x02, 0x02, 0xfc, 0x00, 0xfe, 0x22, 0x22, 0x22, 0x22, 0x1c, 0x00, 0xfc, 0x02, 0x02, 0x02, 0x02, 0xfc, 0x00, 0xfe, 0x22, 0x22, 0x62, 0xa2, 0x1c, 0x00, 0x1c, 0x22, 0x22, 0x42, 0x42, 0x8c, 0x00, 0x02, 0x02, 0x02, 0xfe, 0x02, 0x02, 0x02, 0xfe, 0x00, 0x00, 0x00, 0x00, 0xfe, 0x00, 0x0e, 0x70, 0x80, 0x00, 0x80, 0x70, 0x0e, 0xfe, 0x80, 0x60, 0x60, 0x80, 0xfe, 0x00, 0x06, 0x98, 0x60, 0x60, 0x98, 0x06, 0x00, 0x06, 0x18, 0x20, 0xc0, 0x20, 0x18, 0x06, 0x02, 0x82, 0x42, 0x22, 0x12, 0x0e, 0x00, 0x00, 0x00, 0x00, 0xff, 0x01, 0x01, 0x00, 0x06, 0x08, 0x30, 0xc0, 0x00, 0x00, 0x00, 0x01, 0x01, 0xff, 0x00, 0x00, 0x00, 0x00, 0x04, 0x02, 0x01, 0x01, 0x02, 0x04, 0x00, 0x00, 0x00, 0x00, 0x00, 0x00, 0x00, 0x00, 0x00, 0x01, 0x02, 0x04, 0x00, 0x00, 0x00, 0x90, 0x48, 0x48, 0x48, 0x48, 0xf0, 0x00, 0xff, 0x10, 0x08, 0x08, 0x08, 0xf0, 0x00, 0xf0, 0x08, 0x08, 0x08, 0x08, 0x10, 0x00, 0xf0, 0x08, 0x08, 0x08, 0x10, 0xff, 0x00, 0xf0, 0x48, 0x48, 0x48, 0x48, 0x70, 0x00, 0x10, 0x10, 0xfe, 0x11, 0x11, 0x00, 0x00, 0x70, 0x88, 0x88, 0x88, 0x70, 0x0c, 0x00, 0xff, 0x10, 0x08, 0x08, 0x08, 0xf0, 0x00, 0x00, 0x00, 0x08, 0xfb, 0x00, 0x00, 0x00, 0x00, 0x00, 0x00, 0x08, 0xfb, 0x00, 0x00, 0xff, 0x40, 0xa0, 0x10, 0x08, 0x00, 0x00, 0x00, 0x00, 0x01, 0xff, 0x00, 0x00, 0x00, 0xf8, 0x08, 0x08, 0xf0, 0x08, 0x08, 0xf0, 0xf8, 0x10, 0x08, 0x08, 0x08, 0xf0, 0x00, 0xf0, 0x08, 0x08, 0x08, 0x08, 0xf0, 0x00, 0xf8, 0x10, 0x08, 0x08, 0x08, 0xf0, 0x00, 0xf0, 0x08, 0x08, 0x08, 0x10, 0xf8, 0x00, 0xf8, 0x10, 0x08, 0x08, 0x08, 0x30, 0x00, 0x30, 0x48, 0x48, 0x88, 0x88, 0x10, 0x00, 0x10, 0x10, 0xfe, 0x10, 0x10, 0x00, 0x00, 0xf8, 0x00, 0x00, 0x00, 0x00, 0xf8, 0x00, 0x38, 0xc0, 0x00, 0x00, 0xc0, 0x38, 0x00, 0xf8, 0x00, 0x00, 0xf0, 0x00, 0x00, 0xf8, 0x18, 0x20, 0xc0, 0xc0, 0x20, 0x18, 0x00, 0xf8, 0x00, 0x00, 0x00, 0x00, 0xf8, 0x00, 0x08, 0x08, 0x88, 0x48, 0x28, 0x18, 0x00, 0x00, 0x40, 0xa6, 0x19, 0x01, 0x00, 0x00, 0x00, 0x00, 0x00, 0xff, 0x00, 0x00, 0x00, 0x00, 0x01, 0x19, 0xa6, 0x40, 0x00, 0x00, 0x06, 0x01, 0x01, 0x02, 0x04, 0x04, 0x03, 0x00, 0x00, 0x00, 0x06, 0x00, 0x00, 0x00, 0x00, 0x00, 0x00, 0x00, 0x00, 0x00, 0x00, 0x07, 0x00, 0x00, 0x07, 0x00, 0x00, 0x00, 0x01, 0x02, 0x02, 0x07, 0x02, 0x02, 0x01, 0x04, 0x03, 0x00, 0x03, 0x04, 0x04, 0x03, 0x03, 0x04, 0x04, 0x04, 0x02, 0x03, 0x04, 0x00, 0x00, 0x00, 0x00, 0x00, 0x00, 0x00, 0x00, 0x00, 0x01, 0x06, 0x08, 0x00, 0x00, 0x00, 0x08, 0x06, 0x01, 0x00, 0x00, 0x00, 0x01, 0x00, 0x00, 0x03, 0x00, 0x00, 0x01, 0x00, 0x00, 0x00, 0x03, 0x00, 0x00, 0x00, 0x00, 0x00, 0x12, 0x0e, 0x00, 0x00, 0x00, 0x00, 0x00, 0x00, 0x00, 0x00, 0x00, 0x00, 0x00, 0x00, 0x06, 0x06, 0x00, 0x00, 0x00, 0x06, 0x01, 0x00, 0x00, 0x00, 0x00, 0x00, 0x01, 0x02, 0x04, 0x04, 0x02, 0x01, 0x00, 0x00, 0x04, 0x04, 0x07, 0x04, 0x04, 0x00, 0x07, 0x04, 0x04, 0x04, 0x04, 0x04, 0x00, 0x03, 0x04, 0x04, 0x04, 0x04, 0x03, 0x00, 0x00, 0x00, 0x00, 0x00, 0x07, 0x00, 0x00, 0x02, 0x04, 0x04, 0x04, 0x04, 0x03, 0x00, 0x03, 0x04, 0x04, 0x04, 0x04, 0x03, 0x00, 0x00, 0x00, 0x00, 0x07, 0x00, 0x00, 0x00, 0x03, 0x04, 0x04, 0x04, 0x04, 0x03, 0x00, 0x00, 0x04, 0x04, 0x04, 0x02, 0x01, 0x00, 0x00, 0x00, 0x03, 0x03, 0x00, 0x00, 0x00, 0x00, 0x00, 0x09, 0x07, 0x00, 0x00, 0x00, 0x00, 0x00, 0x00, 0x01, 0x02, 0x04, 0x00, 0x01, 0x01, 0x01, 0x01, 0x01, 0x01, 0x00, 0x04, 0x02, 0x01, 0x00, 0x00, 0x00, 0x00, 0x00, 0x00, 0x00, 0x06, 0x00, 0x00, 0x00, 0x01, 0x02, 0x04, 0x05, 0x05, 0x05, 0x00, 0x07, 0x00, 0x00, 0x00, 0x00, 0x07, 0x00, 0x07, 0x04, 0x04, 0x04, 0x04, 0x03, 0x00, 0x03, 0x04, 0x04, 0x04, 0x04, 0x03, 0x00, 0x07, 0x04, 0x04, 0x04, 0x02, 0x01, 0x00, 0x07, 0x04, 0x04, 0x04, 0x04, 0x04, 0x00, 0x07, 0x00, 0x00, 0x00, 0x00, 0x00, 0x00, 0x03, 0x04, 0x04, 0x04, 0x02, 0x07, 0x00, 0x07, 0x00, 0x00, 0x00, 0x00, 0x07, 0x00, 0x00, 0x04, 0x04, 0x07, 0x04, 0x04, 0x00, 0x03, 0x04, 0x04, 0x04, 0x03, 0x00, 0x00, 0x07, 0x00, 0x00, 0x01, 0x02, 0x04, 0x00, 0x07, 0x04, 0x04, 0x04, 0x04, 0x04, 0x00, 0x07, 0x00, 0x00, 0x00, 0x00, 0x07, 0x00, 0x07, 0x00, 0x00, 0x00, 0x03, 0x07, 0x00, 0x03, 0x04, 0x04, 0x04, 0x04, 0x03, 0x00, 0x07, 0x00, 0x00, 0x00, 0x00, 0x00, 0x00, 0x03, 0x06, 0x05, 0x05, 0x06, 0x0b, 0x08, 0x07, 0x00, 0x00, 0x00, 0x01, 0x06, 0x00, 0x03, 0x04, 0x04, 0x04, 0x04, 0x03, 0x00, 0x00, 0x00, 0x00, 0x07, 0x00, 0x00, 0x00, 0x03, 0x04, 0x04, 0x04, 0x04, 0x03, 0x00, 0x00, 0x00, 0x01, 0x06, 0x01, 0x00, 0x00, 0x07, 0x01, 0x00, 0x00, 0x01, 0x07, 0x00, 0x06, 0x01, 0x00, 0x00, 0x01, 0x06, 0x00, 0x00, 0x00, 0x00, 0x07, 0x00, 0x00, 0x00, 0x07, 0x04, 0x04, 0x04, 0x04, 0x04, 0x00, 0x00, 0x00, 0x00, 0x0f, 0x08, 0x08, 0x00, 0x00, 0x00, 0x00, 0x00, 0x01, 0x06, 0x00, 0x08, 0x08, 0x0f, 0x00, 0x00, 0x00, 0x00, 0x00, 0x00, 0x00, 0x00, 0x00, 0x00, 0x00, 0x08, 0x08, 0x08, 0x08, 0x08, 0x08, 0x08, 0x00, 0x00, 0x00, 0x00, 0x00, 0x00, 0x00, 0x03, 0x04, 0x04, 0x04, 0x02, 0x07, 0x00, 0x07, 0x02, 0x04, 0x04, 0x04, 0x03, 0x00, 0x03, 0x04, 0x04, 0x04, 0x04, 0x02, 0x00, 0x03, 0x04, 0x04, 0x04, 0x02, 0x07, 0x00, 0x03, 0x04, 0x04, 0x04, 0x04, 0x02, 0x00, 0x00, 0x00, 0x07, 0x00, 0x00, 0x00, 0x00, 0x0c, 0x13, 0x12, 0x12, 0x12, 0x0c, 0x00, 0x07, 0x00, 0x00, 0x00, 0x00, 0x07, 0x00, 0x00, 0x04, 0x04, 0x07, 0x04, 0x04, 0x00, 0x08, 0x10, 0x10, 0x08, 0x07, 0x00, 0x00, 0x07, 0x00, 0x00, 0x01, 0x02, 0x04, 0x00, 0x00, 0x04, 0x04, 0x07, 0x04, 0x04, 0x00, 0x07, 0x00, 0x00, 0x07, 0x00, 0x00, 0x07, 0x07, 0x00, 0x00, 0x00, 0x00, 0x07, 0x00, 0x03, 0x04, 0x04, 0x04, 0x04, 0x03, 0x00, 0x1f, 0x02, 0x04, 0x04, 0x04, 0x03, 0x00, 0x03, 0x04, 0x04, 0x04, 0x02, 0x1f, 0x00, 0x07, 0x00, 0x00, 0x00, 0x00, 0x00, 0x00, 0x02, 0x04, 0x04, 0x04, 0x04, 0x03, 0x00, 0x00, 0x00, 0x03, 0x04, 0x04, 0x00, 0x00, 0x03, 0x04, 0x04, 0x04, 0x02, 0x07, 0x00, 0x00, 0x01, 0x06, 0x06, 0x01, 0x00, 0x00, 0x03, 0x04, 0x04, 0x03, 0x04, 0x04, 0x03, 0x06, 0x01, 0x00, 0x00, 0x01, 0x06, 0x00, 0x00, 0x11, 0x12, 0x12, 0x11, 0x0f, 0x00, 0x06, 0x05, 0x04, 0x04, 0x04, 0x04, 0x00, 0x00, 0x00, 0x0c, 0x13, 0x10, 0x00, 0x00, 0x00, 0x00, 0x00, 0x1f, 0x00, 0x00, 0x00, 0x00, 0x10, 0x13, 0x0c, 0x00, 0x00, 0x00, 0x00, 0x00, 0x00, 0x00, 0x00, 0x00, 0x00};

// TODO: Pentatonic has unknown licensing, may need to be replaced
static const uint8_t pentatonic[] = {0x3c, 0xfe, 0xee, 0xc7, 0xc7, 0xe6, 0xfe, 0x3c, 0xc0, 0xf0, 0x7c, 0x1f, 0x87, 0x81, 0x80, 0x00, 0x00, 0x00, 0xc0, 0xc0, 0xc0, 0xc0, 0xc0, 0xc0, 0xc0, 0xc0, 0xc0, 0xf0, 0xf8, 0xfc, 0x1e, 0x0f, 0x07, 0x07, 0x07, 0x0f, 0x1e, 0xfc, 0xf8, 0xf0, 0x06, 0xfe, 0xfe, 0xfe, 0x18, 0x1c, 0x1e, 0x0f, 0x07, 0x07, 0x87, 0xce, 0xfe, 0xfc, 0x30, 0x08, 0x0c, 0x1e, 0x0e, 0xc7, 0xc7, 0xc7, 0xc7, 0xfe, 0xfe, 0x3c, 0x00, 0x00, 0xc0, 0xe0, 0xf0, 0x7c, 0x1e, 0xfe, 0xfe, 0xfe, 0x00, 0x00, 0x00, 0xfe, 0xfe, 0xfe, 0xc6, 0xc6, 0xc6, 0xc6, 0xc6, 0xc6, 0x86, 0x00, 0xe0, 0xf8, 0xfc, 0xde, 0xce, 0xc7, 0xc7, 0xc7, 0xce, 0xde, 0x9c, 0x18, 0x06, 0x06, 0x06, 0x06, 0x06, 0x06, 0xc6, 0xf6, 0xfe, 0x3e, 0x0e, 0x00, 0x7c, 0xfe, 0xfe, 0xc6, 0xc7, 0xc7, 0xc7, 0xce, 0xfe, 0xfe, 0x38, 0x70, 0xfc, 0xfe, 0xcf, 0x87, 0x87, 0x07, 0x87, 0x87, 0xfe, 0xfe, 0xf8, 0xff, 0xff, 0xff, 0xe0, 0x70, 0x70, 0x70, 0x70, 0xf0, 0xe0, 0x80, 0xf0, 0xf0, 0xe0, 0x70, 0x70, 0x70, 0x70, 0xf0, 0xe0, 0xe0, 0x70, 0x70, 0x70, 0x70, 0xf0, 0xe0, 0x80, 0x00, 0x00, 0x00, 0x00, 0x60, 0x78, 0x7e, 0x1f, 0x07, 0x0d, 0x3e, 0x7f, 0x63, 0x63, 0x63, 0x7f, 0x3e, 0x0c, 0x01, 0x01, 0x01, 0x01, 0x01, 0x01, 0x01, 0x01, 0x01, 0x0f, 0x1f, 0x3f, 0x78, 0x70, 0x60, 0x60, 0x60, 0x70, 0x78, 0x3f, 0x1f, 0x0f, 0x00, 0x7f, 0x7f, 0x7f, 0x78, 0x7c, 0x7e, 0x7e, 0x77, 0x77, 0x73, 0x71, 0x71, 0x70, 0x70, 0x18, 0x38, 0x78, 0x70, 0x61, 0x61, 0x61, 0x61, 0x73, 0x7f, 0x3f, 0x1e, 0x1f, 0x1f, 0x1d, 0x1c, 0x1c, 0x1c, 0x7f, 0x7f, 0x7f, 0x1c, 0x1c, 0x18, 0x38, 0x79, 0x70, 0x60, 0xe0, 0xe0, 0x60, 0x79, 0x7f, 0x3f, 0x06, 0x07, 0x3f, 0x7f, 0x71, 0x60, 0xe0, 0xe0, 0xe0, 0x71, 0x7b, 0x3f, 0x1f, 0x00, 0x00, 0x40, 0x70, 0x7c, 0x7f, 0x1f, 0x03, 0x00, 0x00, 0x00, 0x1e, 0x3f, 0x7f, 0x73, 0x61, 0xe1, 0xe1, 0xe1, 0x71, 0x7f, 0x3f, 0x1f, 0x00, 0x19, 0x39, 0x7b, 0x73, 0x63, 0x63, 0x73, 0x71, 0x3f, 0x1f, 0x0f, 0x7f, 0x7f, 0x7f, 0x00, 0x00, 0x00, 0x00, 0x00, 0x7f, 0x7f, 0x7f, 0x7f, 0x7f, 0x7f, 0x00, 0x00, 0x00, 0x00, 0x7f, 0x7f, 0x7f, 0x00, 0x00, 0x00, 0x00, 0x7f, 0x7f, 0x7f};
static const uint8_t pentatonic_point[] = {0x25, 0x2d, 0x30, 0x31, 0x32, 0x33, 0x34, 0x35, 0x36, 0x37, 0x38, 0x39, 0x68, 0x6d};
static const uint8_t pentatonic_width[] = {18, 9, 13, 4, 11, 11, 12, 12, 12, 11, 12, 12, 11, 17};

static const uint8_t battery[] = {0xfe, 0x02, 0x02, 0x02, 0x02, 0x02, 0x02, 0x02, 0x02, 0x02, 0x02, 0x02, 0x02, 0x02, 0x02, 0x02, 0x02, 0x02, 0x02, 0x02, 0x02, 0x02, 0x02, 0x02, 0x02, 0x02, 0x02, 0x02, 0x02, 0xfe, 0xf8, 0xf8, 0x07, 0x04, 0x04, 0x04, 0x04, 0x04, 0x04, 0x04, 0x04, 0x04, 0x04, 0x04, 0x04, 0x04, 0x04, 0x04, 0x04, 0x04, 0x04, 0x04, 0x04, 0x04, 0x04, 0x04, 0x04, 0x04, 0x04, 0x04, 0x04, 0x07, 0x01, 0x01, 0xfe, 0x02, 0xfa, 0xfa, 0xe2, 0x82, 0x02, 0x02, 0x02, 0x02, 0x02, 0x02, 0x02, 0x02, 0x02, 0x02, 0x02, 0x02, 0x02, 0x02, 0x02, 0x02, 0x02, 0x02, 0x02, 0x02, 0x02, 0x02, 0x02, 0xfe, 0xf8, 0xf8, 0x07, 0x04, 0x05, 0x05, 0x05, 0x05, 0x04, 0x04, 0x04, 0x04, 0x04, 0x04, 0x04, 0x04, 0x04, 0x04, 0x04, 0x04, 0x04, 0x04, 0x04, 0x04, 0x04, 0x04, 0x04, 0x04, 0x04, 0x04, 0x04, 0x07, 0x01, 0x01, 0xfe, 0x02, 0xfa, 0xfa, 0xe2, 0x9a, 0x7a, 0xfa, 0xfa, 0xfa, 0xe2, 0x82, 0x02, 0x02, 0x02, 0x02, 0x02, 0x02, 0x02, 0x02, 0x02, 0x02, 0x02, 0x02, 0x02, 0x02, 0x02, 0x02, 0x02, 0xfe, 0xf8, 0xf8, 0x07, 0x04, 0x05, 0x05, 0x05, 0x05, 0x04, 0x05, 0x05, 0x05, 0x05, 0x05, 0x04, 0x04, 0x04, 0x04, 0x04, 0x04, 0x04, 0x04, 0x04, 0x04, 0x04, 0x04, 0x04, 0x04, 0x04, 0x04, 0x04, 0x07, 0x01, 0x01, 0xfe, 0x02, 0xfa, 0xfa, 0xe2, 0x9a, 0x7a, 0xfa, 0xfa, 0xfa, 0xe2, 0x9a, 0x7a, 0xfa, 0xfa, 0xfa, 0xfa, 0xfa, 0xfa, 0xfa, 0xfa, 0xfa, 0xfa, 0xfa, 0xfa, 0xfa, 0xfa, 0xfa, 0x02, 0xfe, 0xf8, 0xf8, 0x07, 0x04, 0x05, 0x05, 0x05, 0x05, 0x04, 0x05, 0x05, 0x05, 0x05, 0x05, 0x04, 0x05, 0x05, 0x05, 0x05, 0x05, 0x05, 0x05, 0x05, 0x05, 0x05, 0x05, 0x05, 0x05, 0x05, 0x05, 0x04, 0x07, 0x01, 0x01};
```

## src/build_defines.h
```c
/*
	SlimeVR Code is placed under the MIT license
	Copyright (c) 2025 SlimeVR Contributors

	Permission is hereby granted, free of charge, to any person obtaining a copy
	of this software and associated documentation files (the "Software"), to deal
	in the Software without restriction, including without limitation the rights
	to use, copy, modify, merge, publish, distribute, sublicense, and/or sell
	copies of the Software, and to permit persons to whom the Software is
	furnished to do so, subject to the following conditions:

	The above copyright notice and this permission notice shall be included in
	all copies or substantial portions of the Software.

	THE SOFTWARE IS PROVIDED "AS IS", WITHOUT WARRANTY OF ANY KIND, EXPRESS OR
	IMPLIED, INCLUDING BUT NOT LIMITED TO THE WARRANTIES OF MERCHANTABILITY,
	FITNESS FOR A PARTICULAR PURPOSE AND NONINFRINGEMENT. IN NO EVENT SHALL THE
	AUTHORS OR COPYRIGHT HOLDERS BE LIABLE FOR ANY CLAIM, DAMAGES OR OTHER
	LIABILITY, WHETHER IN AN ACTION OF CONTRACT, TORT OR OTHERWISE, ARISING FROM,
	OUT OF OR IN CONNECTION WITH THE SOFTWARE OR THE USE OR OTHER DEALINGS IN
	THE SOFTWARE.
*/
#include "sensor/sensors_enum.h"
#include "system/status.h"

#include "app_version.h"

#ifdef CONFIG_NCS_APPLICATION_BOOT_BANNER_STRING
#define FW_NAME CONFIG_NCS_APPLICATION_BOOT_BANNER_STRING
#else
#define FW_NAME "SlimeNRF Tracker"
#endif
#define FW_VERSION_MAJOR APP_VERSION_MAJOR
#define FW_VERSION_MINOR APP_VERSION_MINOR
#define FW_VERSION_PATCH APP_PATCHLEVEL

static uint8_t get_server_constant_imu_id(int id) __unused;
static uint8_t get_server_constant_mag_id(int id) __unused;
static uint8_t get_server_constant_tracker_status(int status) __unused;

// constants from server, should include BoardType, MCUType, IMUType, MagType (not yet)
// https://github.com/SlimeVR/SlimeVR-Server/blob/main/server/core/src/main/java/dev/slimevr/tracking/trackers/udp/FirmwareConstants.kt
#define SVR_IMU_UNKNOWN 0
#define SVR_IMU_MPU9250 1
#define SVR_IMU_MPU6500 2
#define SVR_IMU_BNO080 3
#define SVR_IMU_BNO085 4
#define SVR_IMU_BNO055 5
#define SVR_IMU_MPU6050 6
#define SVR_IMU_BNO086 7
#define SVR_IMU_BMI160 8
#define SVR_IMU_ICM20948 9
#define SVR_IMU_ICM42688 10
#define SVR_IMU_BMI270 11
#define SVR_IMU_LSM6DS3TRC 12
#define SVR_IMU_LSM6DSV 13
#define SVR_IMU_LSM6DSO 14
#define SVR_IMU_LSM6DSR 15
#define SVR_IMU_ICM45686 16
#define SVR_IMU_ICM45605 17
#define SVR_IMU_ADC_RESISTANCE 18
#define SVR_IMU_DEV_RESERVED 250

#define SVR_BOARD_UNKNOWN 0
#define SVR_BOARD_SLIMEVR_LEGACY 1
#define SVR_BOARD_SLIMEVR_DEV 2
#define SVR_BOARD_NODEMCU 3
#define SVR_BOARD_CUSTOM 4
#define SVR_BOARD_WROOM32 5
#define SVR_BOARD_WEMOSD1MINI 6
#define SVR_BOARD_TTGO_TBASE 7
#define SVR_BOARD_ESP01 8
#define SVR_BOARD_SLIMEVR 9
#define SVR_BOARD_LOLIN_C3_MINI 10
#define SVR_BOARD_BEETLE32C32 11
#define SVR_BOARD_ES32C3DEVKITM1 12
#define SVR_BOARD_OWOTRACK 13
#define SVR_BOARD_WRANGLER 14
#define SVR_BOARD_MOCOPI 15
#define SVR_BOARD_WEMOSWROOM02 16
#define SVR_BOARD_XIAO_ESP32C3 17
#define SVR_BOARD_HARITORA 18
#define SVR_BOARD_ESP32C6DEVKITC1 19
#define SVR_BOARD_GLOVE_IMU_SLIMEVR_DEV 20
#define SVR_BOARD_GESTURES 21
#define SVR_BOARD_SLIMEVR_V1_2 22
#define SVR_BOARD_ESP32S3_SUPERMINI 23
#define SVR_BOARD_GENERIC_NRF 24
#define SVR_BOARD_SLIMEVR_BUTTERFLY_DEV 25
#define SVR_BOARD_SLIMEVR_BUTTERFLY 26
#define SVR_BOARD_DEV_RESERVED 250

#define SVR_MCU_UNKNOWN 0
#define SVR_MCU_ESP8266 1
#define SVR_MCU_ESP32 2
#define SVR_MCU_OWOTRACK_ANDROID 3
#define SVR_MCU_WRANGLER 4
#define SVR_MCU_OWOTRACK_IOS 5
#define SVR_MCU_ESP32_C3 6
#define SVR_MCU_MOCOPI 7
#define SVR_MCU_HARITORA 8
#define SVR_MCU_NRF52 9
#define SVR_MCU_NRF54L 10
#define SVR_MCU_DEV_RESERVED 250

#define SVR_MAG_STATUS_NOT_SUPPORTED 0
#define SVR_MAG_STATUS_DISABLED 1
#define SVR_MAG_STATUS_ENABLED 2

// https://github.com/SlimeVR/SlimeVR-Server/blob/main/server/core/src/main/java/dev/slimevr/tracking/trackers/TrackerStatus.kt
#define SVR_STATUS_DISCONNECTED 0
#define SVR_STATUS_OK 1
#define SVR_STATUS_BUSY 2
#define SVR_STATUS_ERROR 3
#define SVR_STATUS_OCCLUDED 4
#define SVR_STATUS_TIMED_OUT 5

#if CONFIG_BOARD_SLIMEVRMINI_P1_UF2 || CONFIG_BOARD_SLIMEVRMINI_P2_UF2 || CONFIG_BOARD_SLIMEVRMINI_P3R6_UF2 || CONFIG_BOARD_SLIMEVRMINI_P3R7_UF2 || CONFIG_BOARD_SLIMEVRMINI_P4_UF2 || CONFIG_BOARD_SLIMEVRMINI_P4R9_UF2 || CONFIG_BOARD_SLIMEVRMINI_P4R11_UF2
#define FW_BOARD SVR_BOARD_SLIMEVR_BUTTERFLY_DEV
#elif CONFIG_BOARD_BUTTERFLY_R15_UF2
#define FW_BOARD SVR_BOARD_SLIMEVR_BUTTERFLY
#else
#define FW_BOARD SVR_BOARD_GENERIC_NRF
#endif

#if CONFIG_SOC_SERIES_NRF52X
#define FW_MCU SVR_MCU_NRF52
#elif CONFIG_SOC_SERIES_NRF54LX
#define FW_MCU SVR_MCU_NRF54L
#else
#define FW_MCU 0
#endif

static uint8_t get_server_constant_imu_id(int id)
{
	switch (id)
	{
	case IMU_BMI160:
		return SVR_IMU_BMI160;
	case IMU_BMI270:
		return SVR_IMU_BMI270;
	case IMU_BMI323:
		return 0;
	case IMU_MPU6050:
		return SVR_IMU_MPU6050;
	case IMU_MPU6500:
		return SVR_IMU_MPU6500;
	case IMU_MPU9250:
		return SVR_IMU_MPU9250;
	case IMU_ICM20948:
		return SVR_IMU_ICM20948;
	case IMU_ICM42688:
		return SVR_IMU_ICM42688;
	case IMU_ICM45686:
		return SVR_IMU_ICM45686;
	case IMU_ICM45688:
		return SVR_IMU_ICM45686; // compatible with driver, but not really
	case IMU_ISM330IS:
		return 0;
	case IMU_LSM6DS3:
		return 0;
	case IMU_LSM6DSM:
		return SVR_IMU_LSM6DS3TRC;
	case IMU_LSM6DSR:
		return SVR_IMU_LSM6DSR;
	case IMU_LSM6DSO:
		return SVR_IMU_LSM6DSO;
	case IMU_LSM6DST:
		return 0;
	case IMU_LSM6DSV:
		return SVR_IMU_LSM6DSV;
	case IMU_ISM330BX:
		return SVR_IMU_LSM6DSV; // not really
	default:
		return SVR_IMU_UNKNOWN;
	}
}

// does not exist in server enums yet
static uint8_t get_server_constant_mag_id(int id)
{
	return SVR_MAG_STATUS_NOT_SUPPORTED;
//	switch (id)
//	{
//	case MAG_HMC5883L:
//		return 0;
//	case MAG_QMC5883L:
//		return 0;
//	case MAG_AK8963:
//		return 0;
//	case MAG_AK09916:
//		return 0;
//	case MAG_AK09940:
//		return 0;
//	case MAG_BMM150:
//		return 0;
//	case MAG_BMM350:
//		return 0;
//	case MAG_IST8306:
//		return 0;
//	case MAG_IST8308:
//		return 0;
//	case MAG_IST8320:
//		return 0;
//	case MAG_IST8321:
//		return 0;
//	case MAG_LIS2MDL:
//		return 0;
//	case MAG_LIS3MDL:
//		return 0;
//	case MAG_MMC34160PJ:
//		return 0;
//	case MAG_MMC3630KJ:
//		return 0;
//	case MAG_MMC5633NJL:
//		return 0;
//	case MAG_MMC5616WA:
//		return 0;
//	case MAG_MMC5983MA:
//		return 0;
//	default:
//		return 0;
//	}
}

static uint8_t get_server_constant_tracker_status(int status)
{
	if (status & (SYS_STATUS_SENSOR_ERROR | SYS_STATUS_SYSTEM_ERROR))
		return SVR_STATUS_ERROR;
	else
		return SVR_STATUS_OK;
}

// https://stackoverflow.com/questions/11697820/how-to-use-date-and-time-predefined-macros-in-as-two-integers-then-stri
#define COMPUTE_BUILD_YEAR \
	( \
		(__DATE__[ 7] - '0') * 1000 + \
		(__DATE__[ 8] - '0') *  100 + \
		(__DATE__[ 9] - '0') *   10 + \
		(__DATE__[10] - '0') \
	)

#define COMPUTE_BUILD_DAY \
	( \
		((__DATE__[4] >= '0') ? (__DATE__[4] - '0') * 10 : 0) + \
		(__DATE__[5] - '0') \
	)

#define BUILD_MONTH_IS_JAN (__DATE__[0] == 'J' && __DATE__[1] == 'a' && __DATE__[2] == 'n')
#define BUILD_MONTH_IS_FEB (__DATE__[0] == 'F')
#define BUILD_MONTH_IS_MAR (__DATE__[0] == 'M' && __DATE__[1] == 'a' && __DATE__[2] == 'r')
#define BUILD_MONTH_IS_APR (__DATE__[0] == 'A' && __DATE__[1] == 'p')
#define BUILD_MONTH_IS_MAY (__DATE__[0] == 'M' && __DATE__[1] == 'a' && __DATE__[2] == 'y')
#define BUILD_MONTH_IS_JUN (__DATE__[0] == 'J' && __DATE__[1] == 'u' && __DATE__[2] == 'n')
#define BUILD_MONTH_IS_JUL (__DATE__[0] == 'J' && __DATE__[1] == 'u' && __DATE__[2] == 'l')
#define BUILD_MONTH_IS_AUG (__DATE__[0] == 'A' && __DATE__[1] == 'u')
#define BUILD_MONTH_IS_SEP (__DATE__[0] == 'S')
#define BUILD_MONTH_IS_OCT (__DATE__[0] == 'O')
#define BUILD_MONTH_IS_NOV (__DATE__[0] == 'N')
#define BUILD_MONTH_IS_DEC (__DATE__[0] == 'D')

#define COMPUTE_BUILD_MONTH \
	( \
		(BUILD_MONTH_IS_JAN) ?  1 : \
		(BUILD_MONTH_IS_FEB) ?  2 : \
		(BUILD_MONTH_IS_MAR) ?  3 : \
		(BUILD_MONTH_IS_APR) ?  4 : \
		(BUILD_MONTH_IS_MAY) ?  5 : \
		(BUILD_MONTH_IS_JUN) ?  6 : \
		(BUILD_MONTH_IS_JUL) ?  7 : \
		(BUILD_MONTH_IS_AUG) ?  8 : \
		(BUILD_MONTH_IS_SEP) ?  9 : \
		(BUILD_MONTH_IS_OCT) ? 10 : \
		(BUILD_MONTH_IS_NOV) ? 11 : \
		(BUILD_MONTH_IS_DEC) ? 12 : \
		/* error default */  99 \
	)

#define COMPUTE_BUILD_HOUR ((__TIME__[0] - '0') * 10 + __TIME__[1] - '0')
#define COMPUTE_BUILD_MIN  ((__TIME__[3] - '0') * 10 + __TIME__[4] - '0')
#define COMPUTE_BUILD_SEC  ((__TIME__[6] - '0') * 10 + __TIME__[7] - '0')

#define BUILD_DATE_IS_BAD (__DATE__[0] == '?')

#define BUILD_YEAR  ((BUILD_DATE_IS_BAD) ? 99 : COMPUTE_BUILD_YEAR)
#define BUILD_MONTH ((BUILD_DATE_IS_BAD) ? 99 : COMPUTE_BUILD_MONTH)
#define BUILD_DAY   ((BUILD_DATE_IS_BAD) ? 99 : COMPUTE_BUILD_DAY)

#define BUILD_TIME_IS_BAD (__TIME__[0] == '?')

#define BUILD_HOUR  ((BUILD_TIME_IS_BAD) ? 99 :  COMPUTE_BUILD_HOUR)
#define BUILD_MIN   ((BUILD_TIME_IS_BAD) ? 99 :  COMPUTE_BUILD_MIN)
#define BUILD_SEC   ((BUILD_TIME_IS_BAD) ? 99 :  COMPUTE_BUILD_SEC)

#define BUILD_TIMESTAMP (((((((BUILD_YEAR - 2020) & 127) * 12 + (BUILD_MONTH & 15)) * 31 + (BUILD_DAY & 31)) * 24 + (BUILD_HOUR & 24)) * 60 + (BUILD_MIN & 60)) * 60 + (BUILD_SEC & 60))

#define TOSTRING(x) STRINGIFY(x)

#define FW_STRING FW_NAME " " APP_VERSION_EXTENDED_STRING "\n"
```

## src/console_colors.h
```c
/*
        SlimeVR Code is placed under the MIT license
        Copyright (c) 2025 SlimeVR Contributors

        Permission is hereby granted, free of charge, to any person obtaining a copy
        of this software and associated documentation files (the "Software"), to deal
        in the Software without restriction, including without limitation the rights
        to use, copy, modify, merge, publish, distribute, sublicense, and/or sell
        copies of the Software, and to permit persons to whom the Software is
        furnished to do so, subject to the following conditions:

        The above copyright notice and this permission notice shall be included in
        all copies or substantial portions of the Software.

        THE SOFTWARE IS PROVIDED "AS IS", WITHOUT WARRANTY OF ANY KIND, EXPRESS OR
        IMPLIED, INCLUDING BUT NOT LIMITED TO THE WARRANTIES OF MERCHANTABILITY,
        FITNESS FOR A PARTICULAR PURPOSE AND NONINFRINGEMENT. IN NO EVENT SHALL THE
        AUTHORS OR COPYRIGHT HOLDERS BE LIABLE FOR ANY CLAIM, DAMAGES OR OTHER
        LIABILITY, WHETHER IN AN ACTION OF CONTRACT, TORT OR OTHERWISE, ARISING FROM,
        OUT OF OR IN CONNECTION WITH THE SOFTWARE OR THE USE OR OTHER DEALINGS IN
        THE SOFTWARE.
*/

#pragma once

#define ANSI_COLOR_RESET "\x1B[0m"
#define ANSI_COLOR_RED "\x1B[31m"
#define ANSI_COLOR_ORANGE "\x1B[38;5;208m"
```
